One B-rep face of a CAD part: STEP entity #339.
In plain terms, the planar face has unit normal (1, 0, 0).
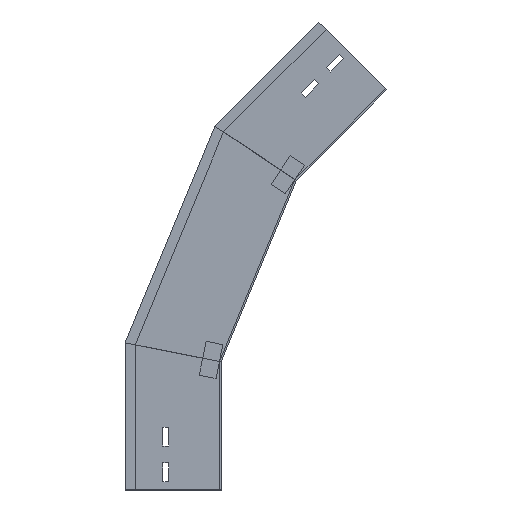
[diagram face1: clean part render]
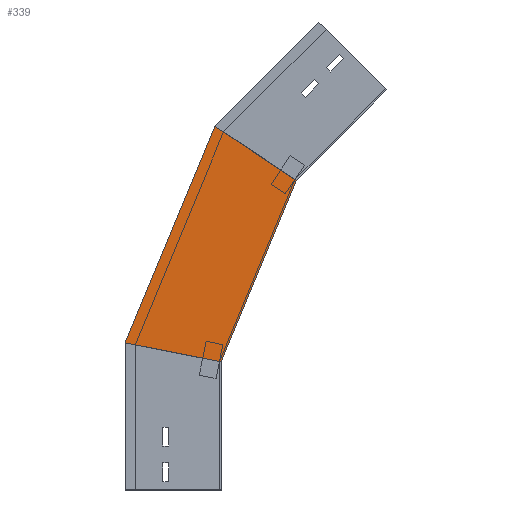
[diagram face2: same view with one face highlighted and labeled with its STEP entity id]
Its self-contained STEP definition (entity closure, numbers rounded to 3 decimals):
#30 = VERTEX_POINT ( 'NONE', #384 ) ;
#62 = LINE ( 'NONE', #1244, #362 ) ;
#63 = LINE ( 'NONE', #985, #994 ) ;
#69 = VECTOR ( 'NONE', #679, 1000. ) ;
#83 = CARTESIAN_POINT ( 'NONE',  ( 0., 112.5, 172.378 ) ) ;
#108 = EDGE_CURVE ( 'NONE', #292, #30, #62, .T. ) ;
#153 = CARTESIAN_POINT ( 'NONE',  ( 0., 9.458, 127.166 ) ) ;
#244 = DIRECTION ( 'NONE',  ( 0., 0., -1. ) ) ;
#292 = VERTEX_POINT ( 'NONE', #83 ) ;
#318 = ORIENTED_EDGE ( 'NONE', *, *, #108, .F. ) ;
#339 = ADVANCED_FACE ( 'NONE', ( #816 ), #1376, .T. ) ;
#362 = VECTOR ( 'NONE', #468, 1000. ) ;
#373 = DIRECTION ( 'NONE',  ( 1., 0., 0. ) ) ;
#384 = CARTESIAN_POINT ( 'NONE',  ( 0., 0., 150. ) ) ;
#418 = DIRECTION ( 'NONE',  ( 0., -0.383, 0.924 ) ) ;
#468 = DIRECTION ( 'NONE',  ( 0., -0.981, -0.195 ) ) ;
#537 = LINE ( 'NONE', #1099, #879 ) ;
#626 = DIRECTION ( 'NONE',  ( 0., -0.831, -0.556 ) ) ;
#649 = CARTESIAN_POINT ( 'NONE',  ( 0., 7.356, 426.218 ) ) ;
#650 = EDGE_CURVE ( 'NONE', #292, #788, #537, .T. ) ;
#677 = EDGE_CURVE ( 'NONE', #788, #1033, #63, .T. ) ;
#679 = DIRECTION ( 'NONE',  ( 0., -0.383, 0.924 ) ) ;
#705 = EDGE_CURVE ( 'NONE', #30, #1033, #768, .T. ) ;
#737 = CARTESIAN_POINT ( 'NONE',  ( 0., -88.017, 362.492 ) ) ;
#768 = LINE ( 'NONE', #1249, #69 ) ;
#788 = VERTEX_POINT ( 'NONE', #649 ) ;
#801 = EDGE_LOOP ( 'NONE', ( #1203, #912, #803, #318 ) ) ;
#803 = ORIENTED_EDGE ( 'NONE', *, *, #705, .F. ) ;
#816 = FACE_OUTER_BOUND ( 'NONE', #801, .T. ) ;
#879 = VECTOR ( 'NONE', #418, 1000. ) ;
#912 = ORIENTED_EDGE ( 'NONE', *, *, #677, .T. ) ;
#985 = CARTESIAN_POINT ( 'NONE',  ( 0., -129.335, 334.885 ) ) ;
#994 = VECTOR ( 'NONE', #626, 1000. ) ;
#1033 = VERTEX_POINT ( 'NONE', #737 ) ;
#1099 = CARTESIAN_POINT ( 'NONE',  ( 0., 113.395, 170.218 ) ) ;
#1203 = ORIENTED_EDGE ( 'NONE', *, *, #650, .T. ) ;
#1214 = AXIS2_PLACEMENT_3D ( 'NONE', #153, #373, #244 ) ;
#1244 = CARTESIAN_POINT ( 'NONE',  ( 0., -28.701, 144.291 ) ) ;
#1249 = CARTESIAN_POINT ( 'NONE',  ( 0., 9.458, 127.166 ) ) ;
#1376 = PLANE ( 'NONE',  #1214 ) ;
